VERSION 5.7 ;
NOWIREEXTENSIONATPIN ON ;
DIVIDERCHAR "/" ;
BUSBITCHARS "[]" ;

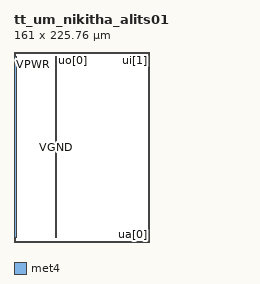
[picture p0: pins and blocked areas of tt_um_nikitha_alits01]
MACRO tt_um_nikitha_alits01
  CLASS BLOCK ;
  FOREIGN tt_um_nikitha_alits01 ;
  ORIGIN 0 0 ;
  SIZE 161.000 BY 225.760 ;

  ########################
  # INPUT PINS (ui[0:7])
  ########################
  PIN ui[0]
    DIRECTION INPUT ;
    USE SIGNAL ;
    PORT LAYER met4 ; RECT 147.510 224.760 147.810 225.760 ; END
  END ui[0]

  PIN ui[1]
    DIRECTION INPUT ;
    USE SIGNAL ;
    PORT LAYER met4 ; RECT 143.830 224.760 144.130 225.760 ; END
  END ui[1]

  PIN ui[2]
    DIRECTION INPUT ;
    USE SIGNAL ;
    PORT LAYER met4 ; RECT 140.150 224.760 140.450 225.760 ; END
  END ui[2]

  PIN ui[3]
    DIRECTION INPUT ;
    USE SIGNAL ;
    PORT LAYER met4 ; RECT 136.470 224.760 136.770 225.760 ; END
  END ui[3]

  PIN ui[4]
    DIRECTION INPUT ;
    USE SIGNAL ;
    PORT LAYER met4 ; RECT 132.790 224.760 133.090 225.760 ; END
  END ui[4]

  PIN ui[5]
    DIRECTION INPUT ;
    USE SIGNAL ;
    PORT LAYER met4 ; RECT 129.110 224.760 129.410 225.760 ; END
  END ui[5]

  PIN ui[6]
    DIRECTION INPUT ;
    USE SIGNAL ;
    PORT LAYER met4 ; RECT 125.430 224.760 125.730 225.760 ; END
  END ui[6]

  PIN ui[7]
    DIRECTION INPUT ;
    USE SIGNAL ;
    PORT LAYER met4 ; RECT 121.750 224.760 122.050 225.760 ; END
  END ui[7]

  ########################
  # OUTPUT PINS (uo[0:5])
  ########################
  PIN uo[0]
    DIRECTION OUTPUT ;
    USE SIGNAL ;
    PORT LAYER met4 ; RECT 70.230 224.760 70.530 225.760 ; END
  END uo[0]

  PIN uo[1]
    DIRECTION OUTPUT ;
    USE SIGNAL ;
    PORT LAYER met4 ; RECT 73.910 224.760 74.210 225.760 ; END
  END uo[1]

  PIN uo[2]
    DIRECTION OUTPUT ;
    USE SIGNAL ;
    PORT LAYER met4 ; RECT 77.590 224.760 77.890 225.760 ; END
  END uo[2]

  PIN uo[3]
    DIRECTION OUTPUT ;
    USE SIGNAL ;
    PORT LAYER met4 ; RECT 81.270 224.760 81.570 225.760 ; END
  END uo[3]

  PIN uo[4]
    DIRECTION OUTPUT ;
    USE SIGNAL ;
    PORT LAYER met4 ; RECT 84.950 224.760 85.250 225.760 ; END
  END uo[4]

  PIN uo[5]
    DIRECTION OUTPUT ;
    USE SIGNAL ;
    PORT LAYER met4 ; RECT 88.630 224.760 88.930 225.760 ; END
  END uo[5]

  ########################
  # ANALOG PINS
  ########################
  PIN ua[0]  # out
    DIRECTION INOUT ;
    USE SIGNAL ;
    PORT LAYER met4 ; RECT 156.560 0.000 157.160 1.000 ; END
  END ua[0]

  PIN ua[1]  # vcon_n
    DIRECTION INOUT ;
    USE SIGNAL ;
    PORT LAYER met4 ; RECT 134.480 0.000 135.080 1.000 ; END
  END ua[1]

  PIN ua[2]  # vcon_p
    DIRECTION INOUT ;
    USE SIGNAL ;
    PORT LAYER met4 ; RECT 112.400 0.000 113.000 1.000 ; END
  END ua[2]

  ########################
  # POWER PINS
  ########################
  PIN VPWR
    DIRECTION INOUT ;
    USE POWER ;
    PORT LAYER met4 ; RECT 1.000 5.000 2.500 220.760 ; END
  END VPWR

  PIN VGND
    DIRECTION INOUT ;
    USE GROUND ;
    PORT LAYER met4 ; RECT 49.000 5.000 50.500 220.760 ; END
  END VGND

END tt_um_nikitha_alits01
END LIBRARY
